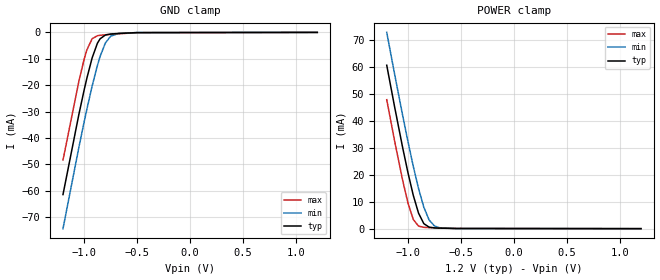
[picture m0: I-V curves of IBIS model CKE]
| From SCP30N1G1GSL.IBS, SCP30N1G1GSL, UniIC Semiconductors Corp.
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|   Model CKE
[Model] CKE
Model_type Input
Vinl =  0.500V
Vinh =  0.700V
C_comp   1.051pF   1.012pF   1.102pF
[Model Spec]
Vinh   0.700V   0.670V   0.750V
Vinl   0.500V   0.470V   0.550V
[Temperature Range]   25.000   85.000   -40.000
[Voltage Range]   1.200V   1.140V   1.300V
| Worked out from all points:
|   GND clamp passes 1 mA (typ) near -0.80 V on its own axis
|   POWER clamp passes 1 mA (typ) near -0.83 V on its own axis
[GND_clamp]
|Voltage   I(typ)   I(min)   I(max)
-1.2V     -61.45mA   -74.36mA   -48.37mA
-1.05V    -31.06mA   -43.53mA   -18.49mA
-1V       -21.76mA   -33.84mA   -10.1mA
-975mV    -17.41mA   -29.17mA   -6.662mA
-925mV    -9.672mA   -20.33mA   -2.402mA
-875mV    -4.095mA   -12.48mA   -1.261mA
-850mV    -2.438mA   -9.114mA   -1.096mA
-800mV    -993uA     -4.017mA   -900uA
-750mV    -614.8uA   -1.44mA    -740.6uA
-675mV    -395.6uA   -396.5uA   -521.2uA
-500mV    -81.51uA   -51.5uA    -118.9uA
1.2V      0A         0A         0A
[POWER_clamp]
|Voltage   I(typ)   I(min)   I(max)
-1.2V     60.47mA    72.63mA    47.72mA
-1.125V   44.92mA    57.04mA    32.29mA
-1.05V    30.03mA    41.93mA    17.91mA
-1V       20.75mA    32.28mA    9.545mA
-950mV    12.4mA     23.14mA    3.43mA
-900mV    5.743mA    14.85mA    945.4uA
-850mV    1.85mA     7.933mA    493.1uA
-800mV    563.8uA    3.212mA    379.2uA
-750mV    277.6uA    1.007mA    302.6uA
-700mV    190.1uA    328.5uA    235uA
-550mV    61.33uA    48.95uA    76.59uA
1.2V      0A         0A         0A
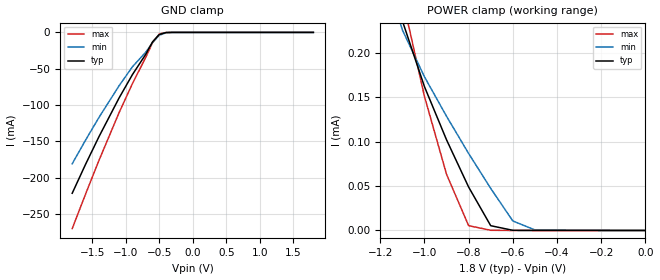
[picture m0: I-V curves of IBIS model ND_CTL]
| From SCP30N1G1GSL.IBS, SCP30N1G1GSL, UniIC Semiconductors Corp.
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|   Model NAND_CTL
[Model]   ND_CTL
Model_type   Input
Vinl =   0.3600V
Vinh =   1.4400V
C_comp   3.14pF   2.83pF   4.09pF
[Temperature Range]   25.0000   85.0000   -40.0000
[Voltage Range]   1.8000V   1.7000V   1.9500V
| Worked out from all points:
|   GND clamp passes 1 mA (typ) near -0.43 V on its own axis
|   POWER clamp passes 1 mA (typ) near -1.80 V on its own axis
[GND_clamp]
| voltage   I(typ)   I(min)   I(max)
-1.8V     -221.2mA   -180.7mA   -269.9mA
-1.6V     -181.3mA   -148mA     -222.2mA
-1.4V     -143.3mA   -116.9mA   -175.9mA
-1.1V     -90.11mA   -73.36mA   -110.3mA
-900mV    -57.9mA    -47.17mA   -70.27mA
-700mV    -29.85mA   -27.03mA   -33.93mA
-600mV    -12.96mA   -13.91mA   -14.02mA
-500mV    -2.882mA   -3.953mA   -2.188mA
-400mV    -217.1uA   -454.4uA   -72.82uA
-300mV    -8.602uA   -33.89uA   -987.1nA
1.8V      152.3pA    2.873nA    75.77pA
[POWER_clamp]
| voltage   I(typ)   I(min)   I(max)
-1.8V     1.005mA    806.7uA    1.303mA
-1.1V     236.4uA    226.1uA    262.5uA
-1V       162.2uA    173.2uA    151.3uA
-900mV    102.2uA    128.7uA    63.39uA
-800mV    48.96uA    86.76uA    5.425uA
-700mV    5.388uA    47.41uA    237.2nA
-600mV    176.2nA    10.73uA    6.493nA
-500mV    5.767nA    594.8nA    208.1pA
0V        0A         0A         0A
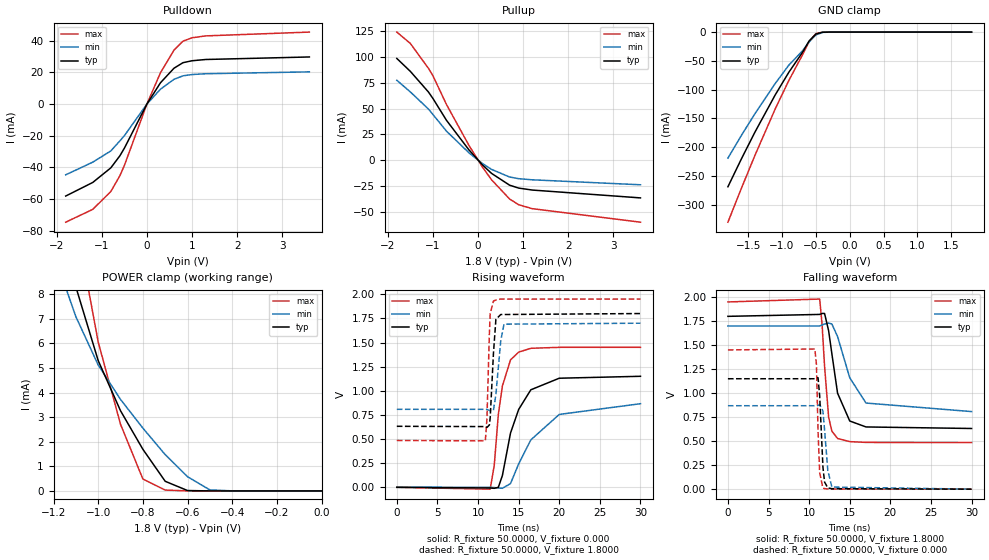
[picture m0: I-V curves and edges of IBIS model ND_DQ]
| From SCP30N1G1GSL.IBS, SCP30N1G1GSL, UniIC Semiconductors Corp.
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|   Model ND_DQ
[Model]   ND_DQ
Model_type   I/O
Polarity   Non-Inverting
Enable   Active-High
Vmeas =   0.9000V
Vinl =   0.3600V
Vinh =   1.4400V
C_comp   3.37pF   3.03pF   4.30pF
[Temperature Range]   25.0000   85.0000   -40.0000
[Voltage Range]   1.8000V   1.7000V   1.9500V
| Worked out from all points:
|   slope of the pulldown table from 0 to 0.27 V, typ, clamps not added: 22.1 ohm
|   slope of the pullup table from 0 to 0.27 V, typ, clamps not added: 23.4 ohm
|   GND clamp passes 1 mA (typ) near -0.42 V on its own axis
|   POWER clamp passes 1 mA (typ) near -0.75 V on its own axis
|   rising waveform, R_fixture 50.0000, V_fixture 0.000: 20-80 % time 2.52ns typ, 4.04ns min, 1.27ns max; typ from 0 V to 1.15 V
|   rising waveform, R_fixture 50.0000, V_fixture 1.8000: 20-80 % time 419ps typ, 580ps min, 303ps max; typ from 0.632 V to 1.8 V
|   falling waveform, R_fixture 50.0000, V_fixture 1.8000: 20-80 % time 1.36ns typ, 2.22ns min, 721ps max; typ from 1.8 V to 0.632 V
|   falling waveform, R_fixture 50.0000, V_fixture 0.000: 20-80 % time 375ps typ, 504ps min, 285ps max; typ from 1.15 V to 0 V
[Pulldown]
| voltage   I(typ)   I(min)   I(max)
-1.8V     -58.1mA    -44.7mA    -74.6mA
-1.2V     -49.5mA    -36.7mA    -66.5mA
-800mV    -40.3mA    -29.6mA    -55.2mA
-600mV    -32.7mA    -23.3mA    -45.3mA
-500mV    -27.9mA    -20mA      -38.8mA
0V        0A         0A         0A
300mV     13.4mA     9.36mA     19.7mA
600mV     22.6mA     15.6mA     34mA
800mV     26.1mA     17.8mA     39.7mA
1V        27.3mA     18.6mA     41.8mA
1.3V      28.1mA     19.1mA     43mA
3.6V      29.7mA     20.3mA     45.4mA
[Pullup]
| voltage   I(typ)   I(min)   I(max)
-1.8V     98.5mA     77.4mA     124mA
-1.5V     86mA       66.1mA     113mA
-1.1V     66.1mA     49.6mA     89mA
-1V       59.8mA     44.3mA     81.8mA
-700mV    38.7mA     28.2mA     54mA
-200mV    9.97mA     7.16mA     14.3mA
100mV     -4.57mA    -3.22mA    -6.73mA
300mV     -12.7mA    -8.82mA    -18.9mA
700mV     -24.1mA    -16.2mA    -37.5mA
900mV     -26.9mA    -17.8mA    -43mA
1.2V      -28.8mA    -18.9mA    -46.8mA
3.6V      -36.4mA    -23.7mA    -59.9mA
[GND_clamp]
| voltage   I(typ)   I(min)   I(max)
-1.8V     -269mA     -219.2mA   -330.6mA
-1.6V     -220.3mA   -179.5mA   -271.4mA
-1.4V     -173.8mA   -141.8mA   -214.2mA
-1.1V     -109mA     -89.17mA   -133.3mA
-900mV    -69.86mA   -57.52mA   -84.19mA
-700mV    -35.61mA   -32.87mA   -40.07mA
-600mV    -15.33mA   -17.01mA   -16.59mA
-500mV    -3.448mA   -4.873mA   -2.634mA
-400mV    -265.4uA   -557.9uA   -90.82uA
-300mV    -10.64uA   -41.65uA   -1.261uA
1.8V      221.4pA    4.414nA    107pA
[POWER_clamp]
| voltage   I(typ)   I(min)   I(max)
-1.8V     44.81mA    34.65mA    59.69mA
-1.2V     12.2mA     9.687mA    16.8mA
-1.1V     8.301mA    7.091mA    10.97mA
-1V       5.302mA    5.122mA    6.06mA
-900mV    3.261mA    3.722mA    2.71mA
-800mV    1.695mA    2.556mA    484.6uA
-700mV    392.1uA    1.477mA    34.23uA
-600mV    15.14uA    577.4uA    1.674uA
-500mV    619.9nA    42.06uA    41.67nA
-400mV    23.06nA    2.246uA    817.2pA
0V        0A         0A         0A
[Ramp]
| variable   typ   min   max
dV/dt_r   0.6780/2.3961n   0.4522/2.9056n   0.8706/1.2615n
dV/dt_f   0.6995/1.3559n   0.5246/2.0930n   0.8786/0.7189n
R_load = 50.0000
[Rising Waveform]
R_fixture = 50.0000
V_fixture = 0.000
V_fixture_min = 0.000
V_fixture_max = 0.000
| time   V(typ)   V(min)   V(max)
0s        0V         0V         0V
11.5ns    -7.06mV    316uV      -19.3mV
12ns      -10.6mV    -2.63mV    230mV
12.5ns    -42.5uV    -7.5mV     755mV
13ns      122mV      -10.1mV    1.05V
14ns      562mV      38.7mV     1.32V
15ns      806mV      242mV      1.4V
16.5ns    1.01V      491mV      1.44V
20ns      1.13V      755mV      1.45V
30ns      1.15V      866mV      1.45V
[Rising Waveform]
R_fixture = 50.0000
V_fixture = 1.8000
V_fixture_min = 1.7000
V_fixture_max = 1.9500
| time   V(typ)   V(min)   V(max)
0s        632mV      808mV      485mV
10.9ns    629mV      808mV      481mV
11.1ns    620mV      807mV      714mV
11.4ns    646mV      797mV      1.6V
11.5ns    722mV      792mV      1.8V
11.9ns    1.39V      797mV      1.93V
12.2ns    1.74V      963mV      1.94V
12.8ns    1.79V      1.52V      1.95V
13.2ns    1.79V      1.69V      1.95V
30ns      1.8V       1.7V       1.95V
[Falling Waveform]
R_fixture = 50.0000
V_fixture = 1.8000
V_fixture_min = 1.7000
V_fixture_max = 1.9500
| time   V(typ)   V(min)   V(max)
0s        1.8V       1.7V       1.95V
11.3ns    1.82V      1.7V       1.98V
11.6ns    1.83V      1.71V      1.71V
11.9ns    1.83V      1.72V      1.28V
12.4ns    1.65V      1.73V      750mV
12.8ns    1.41V      1.72V      604mV
13.5ns    1V         1.59V      528mV
15ns      710mV      1.16V      495mV
17ns      648mV      897mV      487mV
30ns      632mV      808mV      485mV
[Falling Waveform]
R_fixture = 50.0000
V_fixture = 0.000
V_fixture_min = 0.000
V_fixture_max = 0.000
| time   V(typ)   V(min)   V(max)
0s        1.15V      869mV      1.45V
10.7ns    1.15V      869mV      1.46V
10.9ns    1.16V      869mV      1.3V
11.1ns    1.16V      872mV      598mV
11.3ns    967mV      882mV      170mV
11.7ns    229mV      813mV      10.7mV
11.9ns    74.1mV     618mV      5.78mV
12.3ns    13.3mV     194mV      2.12mV
12.8ns    4.97mV     22.1mV     885uV
30ns      4.24uV     -1.96uV    -20.9uV
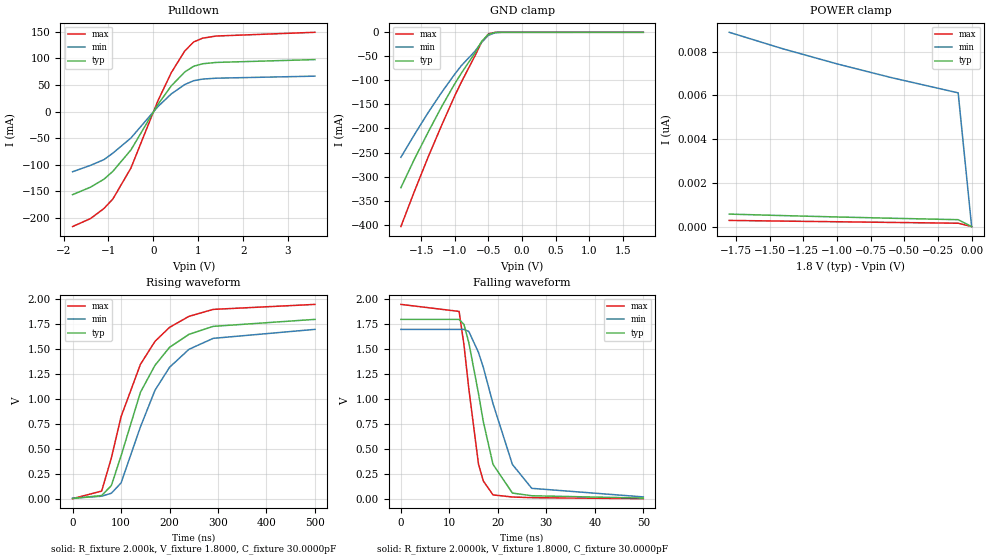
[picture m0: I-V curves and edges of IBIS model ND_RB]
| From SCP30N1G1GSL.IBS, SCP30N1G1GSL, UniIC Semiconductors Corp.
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|   Model RBb_BUF
[Model]   ND_RB
Model_type   Open_drain
Polarity   Non-Inverting
Enable   Active-High
Vmeas =   0.9000V
Cref =  30.0000pF
Rref =   2.0000k
Vref =   1.8000V
C_comp   3.29pF   2.96pF   4.14pF
[Temperature Range]   25.0000   85.0000   -40.0000
[Voltage Range]   1.8000V   1.7000V   1.9500V
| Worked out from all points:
|   slope of the pulldown table from 0 to 0.27 V, typ, clamps not added: 7.92 ohm
|   GND clamp passes 1 mA (typ) near -0.42 V on its own axis
|   rising waveform, R_fixture 2.000k, V_fixture 1.8000, C_fixture 30.0000pF: 20-80 % time 89ns typ, 92.2ns min, 88.1ns max; typ from 0.007 V to 1.8 V
|   falling waveform, R_fixture 2.0000k, V_fixture 1.8000, C_fixture 30.0000pF: 20-80 % time 4.36ns typ, 6.21ns min, 2.91ns max; typ from 1.8 V to 0.013 V
[Pulldown]
| voltage   I(typ)   I(min)   I(max)
-1.8V     -156mA     -113mA     -216mA
-1.4V     -142mA     -101mA     -201mA
-1.1V     -127mA     -90.2mA    -182mA
-900mV    -112mA     -77.9mA    -164mA
-500mV    -72mA      -49.6mA    -106mA
100mV     13.3mA     9.21mA     20.1mA
400mV     48.4mA     33.3mA     73.3mA
700mV     74.5mA     50.9mA     114mA
900mV     85.3mA     58.1mA     131mA
1.1V      89.9mA     61.1mA     138mA
1.4V      92.4mA     62.8mA     142mA
3.6V      97.7mA     66.6mA     149mA
[POWER_clamp]
| voltage   I(typ)   I(min)   I(max)
-1.8V     570.3pA    8.889nA    280.9pA
-1.4V     501.8pA    8.131nA    250.2pA
-1V       439.3pA    7.445nA    220pA
-600mV    381.7pA    6.821nA    190pA
-100mV    314.9pA    6.118nA    152.7pA
0V        0A         0A         0A
[GND_clamp]
| voltage   I(typ)   I(min)   I(max)
-1.8V     -323mA     -260mA     -404mA
-1.6V     -264mA     -213mA     -331mA
-1.4V     -209mA     -168mA     -261mA
-1.2V     -156mA     -126mA     -195mA
-1V       -107mA     -87mA      -132mA
-900mV    -84.5mA    -69mA      -103mA
-700mV    -43.1mA    -39.4mA    -48.9mA
-600mV    -18.7mA    -20.6mA    -20.4mA
-500mV    -4.31mA    -6.24mA    -3.33mA
-400mV    -343uA     -733uA     -120uA
-300mV    -13.9uA    -54.7uA    -1.7uA
1.8V      302pA      6.12nA     134pA
[Ramp]
| variable   typ   min   max
dV/dt_r   1.08/29n   1.02/37.6n   1.17/22.3n
dV/dt_f   1.08/0.759n   1.02/1.19n   1.17/0.463n
R_load = 50.0000
[Rising Waveform]
R_fixture = 2.000k
V_fixture = 1.8000
V_fixture_min = 1.7000
V_fixture_max = 1.9500
C_fixture = 30.0000pF
| time   V(typ)   V(min)   V(max)
0s        6.56mV     8.95mV     4.73mV
60ns      36.1mV     29.4mV     80.9mV
80ns      136mV      59.1mV     412mV
100ns     433mV      162mV      825mV
140ns     1.07V      724mV      1.35V
170ns     1.34V      1.09V      1.58V
200ns     1.52V      1.32V      1.72V
240ns     1.65V      1.5V       1.83V
290ns     1.73V      1.61V      1.9V
500ns     1.8V       1.7V       1.95V
[Falling Waveform]
R_fixture = 2.0000k
V_fixture = 1.8000
V_fixture_min = 1.7000
V_fixture_max = 1.9500
C_fixture = 30.0000pF
| time   V(typ)   V(min)   V(max)
0s        1.8V       1.7V       1.95V
12ns      1.8V       1.7V       1.88V
13ns      1.75V      1.7V       1.55V
14ns      1.57V      1.68V      1.11V
16ns      1.06V      1.47V      354mV
17ns      777mV      1.32V      184mV
19ns      350mV      957mV      44.4mV
23ns      63mV       349mV      23.4mV
27ns      35.9mV     110mV      16.7mV
50ns      12.6mV     24.4mV     6.75mV
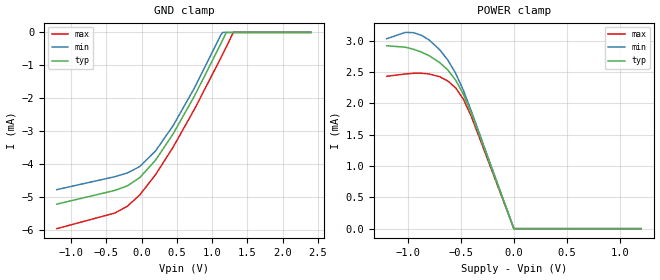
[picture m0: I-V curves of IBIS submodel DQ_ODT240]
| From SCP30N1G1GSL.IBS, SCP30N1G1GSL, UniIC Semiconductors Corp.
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|   Submodel DQ_ODT240
[Submodel] DQ_ODT240
Submodel_type Dynamic_clamp
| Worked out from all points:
|   POWER clamp passes 1 mA (typ) near -0.22 V on its own axis
[GND_clamp]
|Voltage   I(typ)   I(min)   I(max)
-1.2V     -5.216mA   -4.775mA   -5.96mA
-375mV    -4.797mA   -4.38mA    -5.484mA
-200mV    -4.66mA    -4.269mA   -5.279mA
-25mV     -4.411mA   -4.074mA   -4.936mA
200mV     -3.875mA   -3.597mA   -4.318mA
450mV     -3.072mA   -2.823mA   -3.476mA
750mV     -1.931mA   -1.685mA   -2.331mA
1.125V    -335.4uA   -67.96uA   -766.2uA
1.15V     -224.1uA   0A         -657.9uA
1.2V      0A         0A         -440.2uA
1.3V      0A         0A         0A
2.4V      0A         0A         0A
[POWER_clamp]
|Voltage   I(typ)   I(min)   I(max)
-1.2V     2.92mA     3.033mA    2.433mA
-1.025V   2.898mA    3.134mA    2.471mA
-950mV    2.866mA    3.13mA     2.481mA
-875mV    2.821mA    3.09mA     2.482mA
-800mV    2.762mA    3.013mA    2.47mA
-700mV    2.652mA    2.857mA    2.426mA
-625mV    2.536mA    2.695mA    2.36mA
-550mV    2.373mA    2.482mA    2.249mA
-475mV    2.14mA     2.202mA    2.063mA
-400mV    1.833mA    1.87mA     1.785mA
0V        -796.2fA   -3.949pA   1.564pA
1.2V      0A         0A         0A
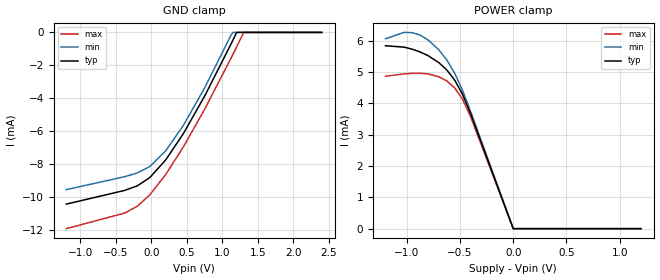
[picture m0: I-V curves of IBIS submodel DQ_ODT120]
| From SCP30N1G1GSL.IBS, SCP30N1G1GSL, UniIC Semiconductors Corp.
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|   Submodel DQ_ODT120
[Submodel] DQ_ODT120
Submodel_type Dynamic_clamp
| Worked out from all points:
|   POWER clamp passes 1 mA (typ) near -0.11 V on its own axis
[GND_clamp]
|Voltage   I(typ)   I(min)   I(max)
-1.2V     -10.43mA   -9.55mA    -11.92mA
-375mV    -9.594mA   -8.76mA    -10.97mA
-200mV    -9.321mA   -8.539mA   -10.56mA
-25mV     -8.823mA   -8.148mA   -9.872mA
200mV     -7.75mA    -7.195mA   -8.636mA
450mV     -6.144mA   -5.645mA   -6.953mA
750mV     -3.862mA   -3.37mA    -4.662mA
1.125V    -670.8uA   -135.9uA   -1.532mA
1.15V     -448.2uA   0A         -1.316mA
1.2V      0A         0A         -880.3uA
1.3V      0A         0A         0A
2.4V      0A         0A         0A
[POWER_clamp]
|Voltage   I(typ)   I(min)   I(max)
-1.2V     5.84mA     6.065mA    4.866mA
-1.025V   5.796mA    6.267mA    4.942mA
-950mV    5.732mA    6.26mA     4.961mA
-875mV    5.643mA    6.181mA    4.963mA
-800mV    5.524mA    6.027mA    4.94mA
-700mV    5.305mA    5.714mA    4.851mA
-625mV    5.072mA    5.391mA    4.719mA
-550mV    4.745mA    4.963mA    4.497mA
-475mV    4.28mA     4.405mA    4.127mA
-400mV    3.667mA    3.74mA     3.57mA
0V        -1.592pA   -7.899pA   3.128pA
1.2V      0A         0A         0A
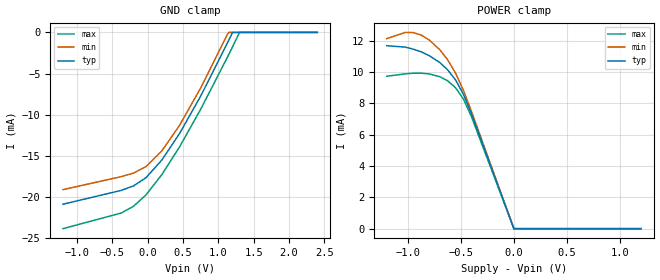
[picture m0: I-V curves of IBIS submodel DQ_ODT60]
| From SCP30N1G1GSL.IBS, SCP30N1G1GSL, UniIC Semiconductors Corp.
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|   Submodel DQ_ODT60
[Submodel] DQ_ODT60
Submodel_type Dynamic_clamp
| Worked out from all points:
|   POWER clamp passes 1 mA (typ) near -0.06 V on its own axis
[GND_clamp]
|Voltage   I(typ)   I(min)   I(max)
-1.2V     -20.87mA   -19.1mA    -23.84mA
-375mV    -19.19mA   -17.52mA   -21.94mA
-200mV    -18.64mA   -17.08mA   -21.11mA
-25mV     -17.65mA   -16.3mA    -19.74mA
200mV     -15.5mA    -14.39mA   -17.27mA
450mV     -12.29mA   -11.29mA   -13.91mA
750mV     -7.723mA   -6.74mA    -9.325mA
1.125V    -1.342mA   -271.9uA   -3.065mA
1.15V     -896.5uA   0A         -2.632mA
1.2V      0A         0A         -1.761mA
1.3V      0A         0A         0A
2.4V      0A         0A         0A
[POWER_clamp]
|Voltage   I(typ)   I(min)   I(max)
-1.2V     11.68mA    12.13mA    9.732mA
-1.025V   11.59mA    12.53mA    9.883mA
-950mV    11.46mA    12.52mA    9.923mA
-875mV    11.29mA    12.36mA    9.927mA
-800mV    11.05mA    12.05mA    9.88mA
-700mV    10.61mA    11.43mA    9.702mA
-625mV    10.14mA    10.78mA    9.439mA
-550mV    9.49mA     9.926mA    8.995mA
-475mV    8.559mA    8.81mA     8.254mA
-400mV    7.334mA    7.48mA     7.141mA
0V        -3.185pA   -15.8pA    6.255pA
1.2V      0A         0A         0A
